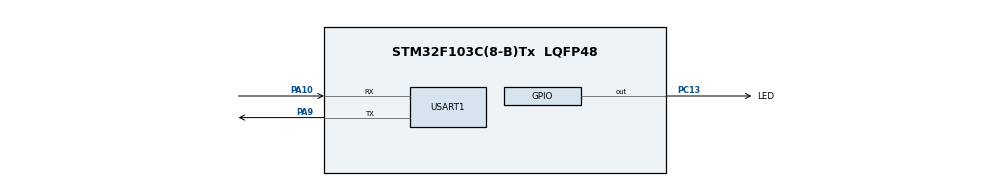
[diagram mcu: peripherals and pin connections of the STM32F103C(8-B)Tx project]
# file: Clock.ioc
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Mcu.Family=STM32F1
Mcu.Name=STM32F103C(8-B)Tx
Mcu.Package=LQFP48
NVIC.PriorityGroup=NVIC_PRIORITYGROUP_2
NVIC.USART1_IRQn=true\:1\:0\:true\:false\:true\:true\:true\:true
PA0-WKUP.GPIO_Label=WK_UP
PA0-WKUP.Mode=SYS_WakeUp0
PA0-WKUP.Signal=SYS_WKUP
PA10.Mode=Asynchronous
PA10.Signal=USART1_RX
PA13.Mode=Serial_Wire
PA13.Signal=SYS_JTMS-SWDIO
PA14.Mode=Serial_Wire
PA14.Signal=SYS_JTCK-SWCLK
PA9.Mode=Asynchronous
PA9.Signal=USART1_TX
PC13-TAMPER-RTC.GPIO_Label=LED
PC13-TAMPER-RTC.GPIO_PuPd=GPIO_PULLUP
PC13-TAMPER-RTC.GPIO_Speed=GPIO_SPEED_FREQ_HIGH
PC13-TAMPER-RTC.PinState=GPIO_PIN_SET
PC13-TAMPER-RTC.Signal=GPIO_Output
PD0-OSC_IN.Mode=HSE-External-Oscillator
PD0-OSC_IN.Signal=RCC_OSC_IN
PD1-OSC_OUT.Mode=HSE-External-Oscillator
PD1-OSC_OUT.Signal=RCC_OSC_OUT
ProjectManager.HeapSize=0x200
ProjectManager.StackSize=0x400
ProjectManager.TargetToolchain=MDK-ARM V5.32
USART1.VirtualMode=VM_ASYNC
board=custom

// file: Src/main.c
/* USER CODE BEGIN Header */
/**
 ******************************************************************************
 * @file           : main.c
 * @brief          : Main program body
 ******************************************************************************
 * @attention
 *
 * Copyright (c) 2024 STMicroelectronics.
 * All rights reserved.
 *
 * This software is licensed under terms that can be found in the LICENSE file
 * in the root directory of this software component.
 * If no LICENSE file comes with this software, it is provided AS-IS.
 *
 ******************************************************************************
 */
/* USER CODE END Header */
#include "main.h"
#include "usart.h"
#include "gpio.h"

void SystemClock_Config(void);

int main(void)
{

	/* MCU Configuration--------------------------------------------------------*/

	/* Reset of all peripherals, Initializes the Flash interface and the Systick. */
	HAL_Init();

	/* Configure the system clock */
	SystemClock_Config();

	/* Initialize all configured peripherals */
	MX_GPIO_Init();
	MX_USART1_UART_Init();
	/* USER CODE BEGIN 2 */

	printf("USART1 Init");
	HAL_UART_Receive_IT(&huart1, &UART1_data, REC_LENGTH);

	/* USER CODE END 2 */

	/* Infinite loop */
	/* USER CODE BEGIN WHILE */
	while (1)
	{
		USART_Close();
		HAL_Delay(100);

		/* USER CODE END WHILE */

	}
}

void SystemClock_Config(void)
{
	RCC_OscInitTypeDef RCC_OscInitStruct = {0};
	RCC_ClkInitTypeDef RCC_ClkInitStruct = {0};

	/** Initializes the RCC Oscillators according to the specified parameters
	 * in the RCC_OscInitTypeDef structure.
	 */
	RCC_OscInitStruct.OscillatorType = RCC_OSCILLATORTYPE_HSE;
	RCC_OscInitStruct.HSEState = RCC_HSE_ON;
	RCC_OscInitStruct.HSEPredivValue = RCC_HSE_PREDIV_DIV1;
	RCC_OscInitStruct.HSIState = RCC_HSI_ON;
	RCC_OscInitStruct.PLL.PLLState = RCC_PLL_ON;
	RCC_OscInitStruct.PLL.PLLSource = RCC_PLLSOURCE_HSE;
	RCC_OscInitStruct.PLL.PLLMUL = RCC_PLL_MUL9;
	if (HAL_RCC_OscConfig(&RCC_OscInitStruct) != HAL_OK)
	{
		Error_Handler();
	}

	/** Initializes the CPU, AHB and APB buses clocks
	 */
	RCC_ClkInitStruct.ClockType = RCC_CLOCKTYPE_HCLK | RCC_CLOCKTYPE_SYSCLK | RCC_CLOCKTYPE_PCLK1 | RCC_CLOCKTYPE_PCLK2;
	RCC_ClkInitStruct.SYSCLKSource = RCC_SYSCLKSOURCE_PLLCLK;
	RCC_ClkInitStruct.AHBCLKDivider = RCC_SYSCLK_DIV1;
	RCC_ClkInitStruct.APB1CLKDivider = RCC_HCLK_DIV2;
	RCC_ClkInitStruct.APB2CLKDivider = RCC_HCLK_DIV1;

	if (HAL_RCC_ClockConfig(&RCC_ClkInitStruct, FLASH_LATENCY_2) != HAL_OK)
	{
		Error_Handler();
	}
}

void Error_Handler(void)
{
	__disable_irq();
	while (1)
	{
	}
}
